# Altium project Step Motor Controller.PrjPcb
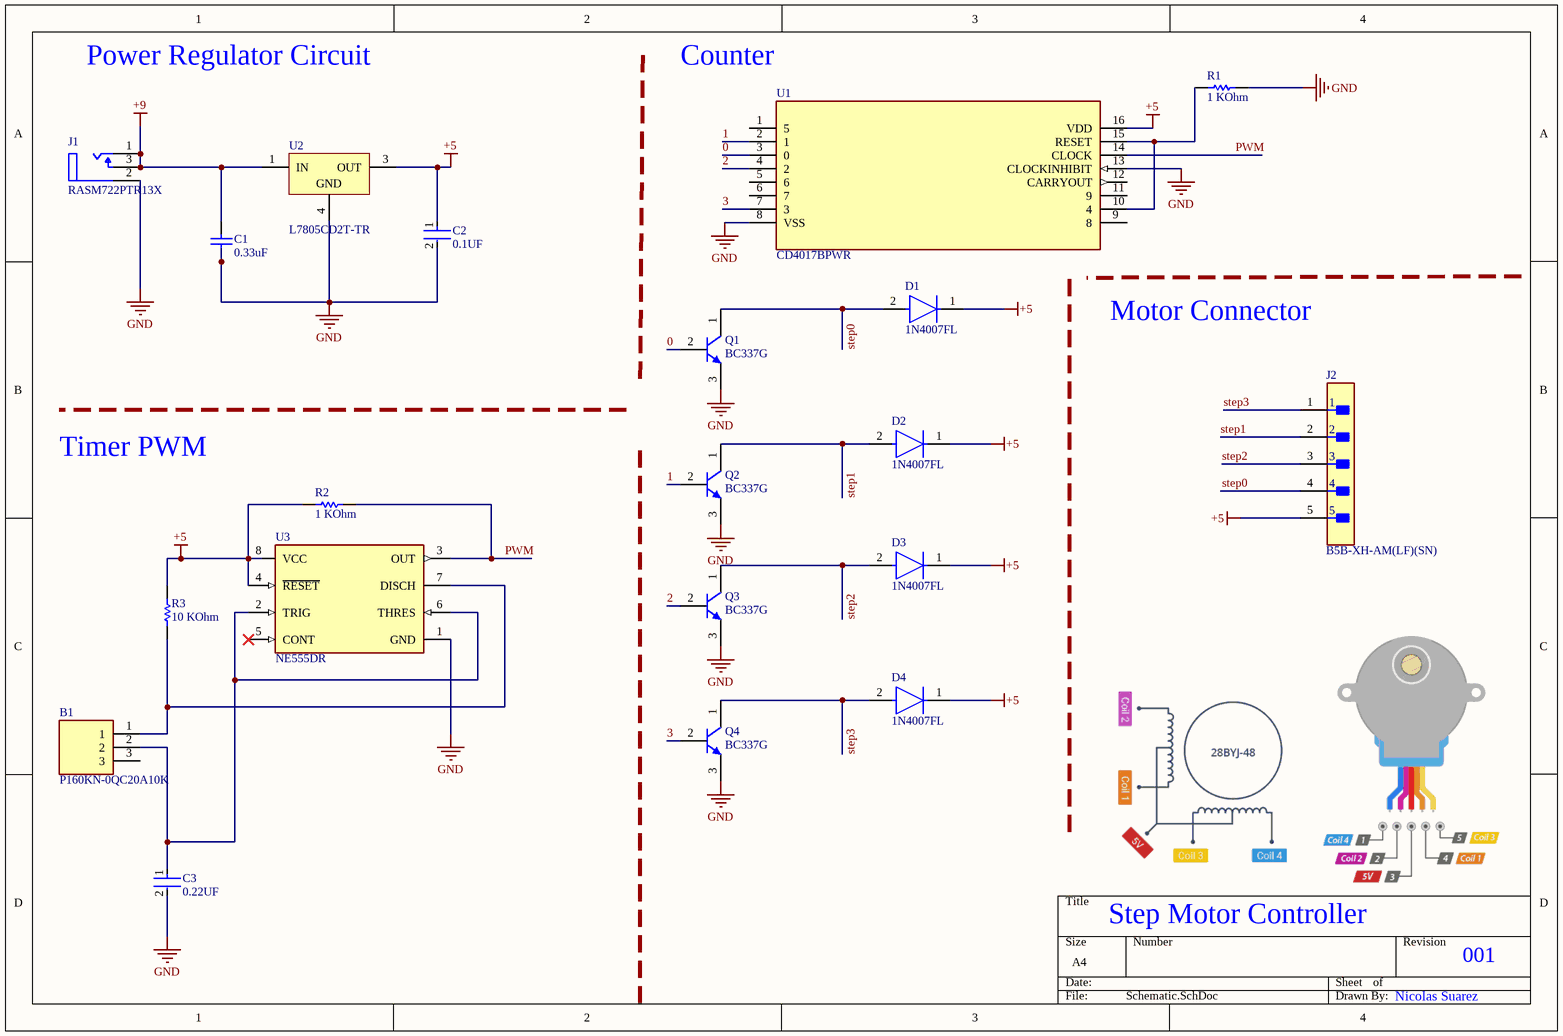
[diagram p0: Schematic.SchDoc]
1 sheet, 20 parts. Net scope: global (net labels, ports and power ports of the same name join across sheets).
Board file: PCB1.PcbDoc

## Sheet Schematic.SchDoc
size A4; SheetNumber: 1; SheetTotal: 1

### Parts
B1  P160KN-0QC20A10K  [P160KN0QC20A10K]
C1  0.33uF  [CAPC2013X95X45ML10T25]
C2  0.1UF  [FP-CC0603-DA-MFG]
C3  0.22UF  [FP-CC0603-DA-MFG]
D1  1N4007FL  [FP-1N4007FL-MFG]
D2  1N4007FL  [FP-1N4007FL-MFG]
D3  1N4007FL  [FP-1N4007FL-MFG]
D4  1N4007FL  [FP-1N4007FL-MFG]
J1  RASM722PTR13X  [FP-RASM722PTR13X-MFG]
J2  B5B-XH-AM(LF)(SN)  [FP-B5B-XH-AM_LF_SN-MFG]
Q1  BC337G  [ONSC-TO-92-3-29-11]
Q2  BC337G  [ONSC-TO-92-3-29-11]
Q3  BC337G  [ONSC-TO-92-3-29-11]
Q4  BC337G  [ONSC-TO-92-3-29-11]
R1  1 KOhm  [RESC2013X60X35ML10T20]
R2  1 KOhm  [RESC2013X60X35ML10T20]
R3  10 KOhm  [RESC2013X60X35NL10T20]
U1  CD4017BPWR  [PW16]
U2  L7805CD2T-TR  [TO-263_M]
U3  NE555DR  [FP-D0008A-IPC_A]

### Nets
+5: C2.1 D1.1(C) D2.1(C) D3.1(C) D4.1(C) J2.5 R2.1 R3.2 U1.16(VDD) U2.3(OUT) U3.4(~{RESET}) U3.8(VCC)
+9: C1.2 J1.1(TIP_TERMINAL(CENTER_PIN)) J1.3(SHUNT_TERMINAL) U2.1(IN)
GND: C1.1 C2.2 C3.2 J1.2(SLEEVE_TERMINAL) Q1.3(E) Q2.3(E) Q3.3(E) Q4.3(E) R1.2 U1.8(VSS) U1.13(CLOCKINHIBIT) U2.4(GND) U3.1(GND)
0: Q1.2(B) U1.3(0)
1: Q2.2(B) U1.2(1)
2: Q3.2(B) U1.4(2)
3: Q4.2(B) U1.7(3)
PWM: R2.2 U1.14(CLOCK) U3.3(OUT)
step0: D1.2(A) J2.4 Q1.1(C)
step1: D2.2(A) J2.2 Q2.1(C)
step2: D3.2(A) J2.3 Q3.1(C)
step3: D4.2(A) J2.1 Q4.1(C)
NetB1_1: B1.1 R3.1 U3.7(DISCH)
NetB1_2: B1.2 C3.1 U3.2(TRIG) U3.6(THRES)
NetR1_1: R1.1 U1.10(4) U1.15(RESET)

Not connected (* = marked no-connect by the designer): B1 3; U1 1(5) 5(6) 6(7) 9(8) 11(9) 12(CARRYOUT); U3 5(CONT)*

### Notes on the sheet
- Power Regulator Circuit
- Counter
- Motor Connector
- Timer PWM
- Step Motor Controller
- 001
- Nicolas Suarez

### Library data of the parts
B1 = P160KN-0QC20A10K: Potentiometers 16mm Rotary Panel Potentiometer; Manufacturer_Name: TT Electronics; Geometry.Height: 20.75mm
C1 = CMP-1036-04606-2: 0.33uFGRM219R71H334KA88D; Manufacturer: Murata
C2 = CMP-2000-05002-2: CAP CER 0.1UF 16V X7R 0603 CC0603KRX7R7BB104; Manufacturer: YAGEO; Tolerance: 0.1; Value: 100 nF; Temperature Coefficient: 15%; Material: Ceramic
C3 = CMP-2000-05002-2: CAP CER 0.22UF 16V X7R 0603; Manufacturer Part Number: CC0603KRX7R7BB104; Manufacturer: YAGEO; Tolerance: 0.1; Temperature Coefficient: 15%; Material: Ceramic
D1-D4 = CMP-10078-122641204-1: 1N4007FL Diode Gen Purp 1KV 1A SOD123FL; Capacitance: 6pF; Max Junction Temperature (Tj): 150°C; Peak Reverse Current: 5µA; Max Forward Surge Current (Ifsm): 30A
J1 = CMP-47995-000002-1: CONN PWR JACK 2.1X5.5MM SOLDER; Shielding: Unshielded; Gender: Male; Current Rating: 5A
J2 = CMP-17439-000304-1: CONN HEADER VERT 5POS 2.5MM; Mated Stacking Heights: 9.8mm; Voltage Rating: 250V; Max Current Rating: 3A; Number of Positions: 5; Contact Resistance: 20mR
Q1-Q4 = CMP-1048-01442-1: Amplifier Transistor, NPN Silicon, 3-Pin TO-92, Pb-Free, Bulk Box; Manufacturer: On Semiconductor; IC Continuous (A): 0.8
R1 R2 = CMP-2100-03671-1: Chip Resistor, 1 KOhm, +/- 1%, 125 mW, -55 to 155 degC, 0805 (2012 Metric), RoHS, Tape and Reel; Manufacturer: Yageo; Temperature Coefficient: 100ppm/degreesC; Voltage Rating (DC): 150V; Max Power Dissipation: 125mW; Resistance: 1KOhm
R3 = CMP-1659-00013-4: Chip Resistor, 10 KOhm, +/- 1%, 0.125 W, -55 to 155 degC, 0805 (2012 Metric), RoHS, Tape and Reel; Manufacturer: Yageo; Voltage Rating: 150 V
U1 = CD4017BPWR: CMOS Decade Counter with 10 Decoded Outputs; MF: Texas Instruments
U2 = CMP-0244-00213-1: Positive Voltage Regulator, 3-Pin D2PAK, Tape and Reel
U3 = CMP-1685-00007-2: IC OSC SGL TIMER 100KHZ 8-SOIC; Low Level Output Current: 200mA; Quiescent Current: 15mA; Min Supply Voltage: 4.5V; Number of Timers/Counters: 1; Max Supply Voltage: 16V; Operating Supply Current: 10mA; High Level Output Current: -200mA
